VERSION 5.8 ;
BUSBITCHARS "[]" ;
DIVIDERCHAR "/" ;
UNITS
    DATABASE MICRONS 1000 ;
END UNITS

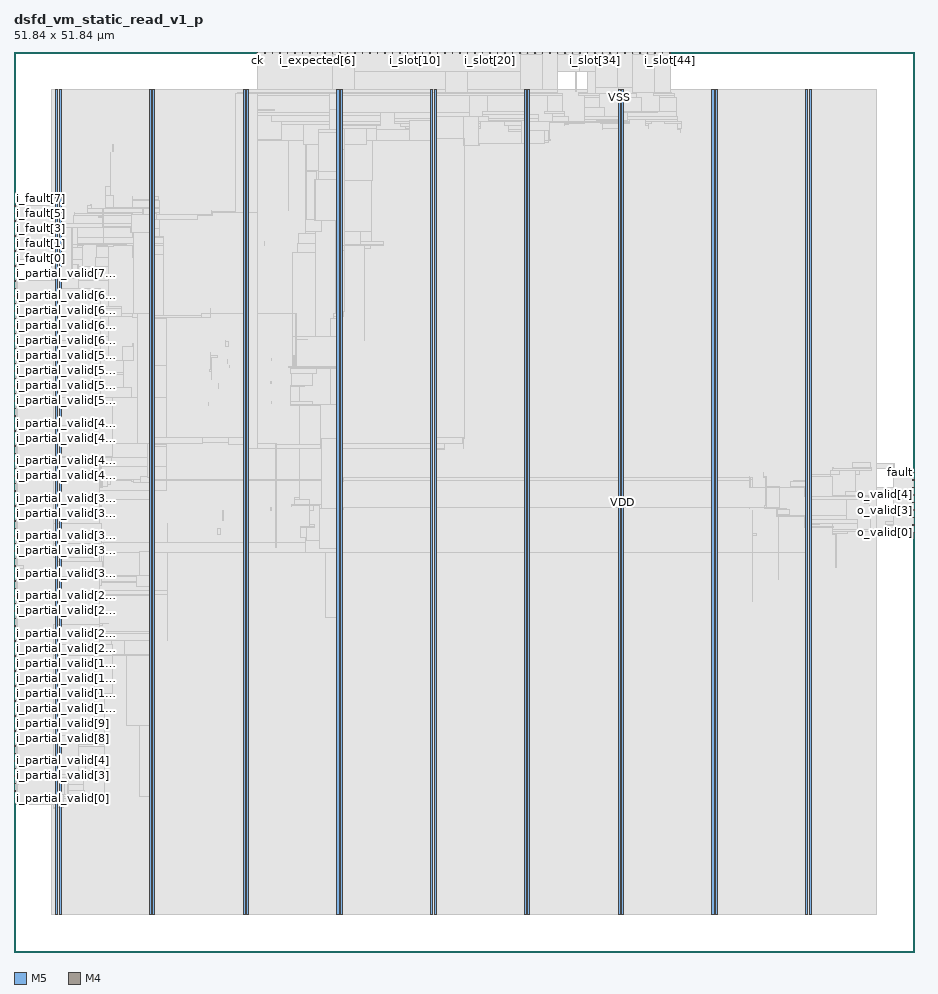
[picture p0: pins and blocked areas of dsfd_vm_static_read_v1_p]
MACRO dsfd_vm_static_read_v1_p
  FOREIGN dsfd_vm_static_read_v1_p 0 0 ;
  CLASS BLOCK ;
  SIZE 51.84 BY 51.84 ;
  PIN ck
    DIRECTION INPUT ;
    USE SIGNAL ;
    PORT
      LAYER M5 ;
        RECT  14.016 51.756 14.04 51.84 ;
    END
  END ck
  PIN fault
    DIRECTION OUTPUT ;
    USE SIGNAL ;
    PORT
      LAYER M4 ;
        RECT  51.756 27.6 51.84 27.624 ;
    END
  END fault
  PIN i_expected[0]
    DIRECTION INPUT ;
    USE SIGNAL ;
    PORT
      LAYER M5 ;
        RECT  14.88 51.756 14.904 51.84 ;
    END
  END i_expected[0]
  PIN i_expected[1]
    DIRECTION INPUT ;
    USE SIGNAL ;
    PORT
      LAYER M5 ;
        RECT  15.312 51.756 15.336 51.84 ;
    END
  END i_expected[1]
  PIN i_expected[2]
    DIRECTION INPUT ;
    USE SIGNAL ;
    PORT
      LAYER M5 ;
        RECT  15.744 51.756 15.768 51.84 ;
    END
  END i_expected[2]
  PIN i_expected[3]
    DIRECTION INPUT ;
    USE SIGNAL ;
    PORT
      LAYER M5 ;
        RECT  16.176 51.756 16.2 51.84 ;
    END
  END i_expected[3]
  PIN i_expected[4]
    DIRECTION INPUT ;
    USE SIGNAL ;
    PORT
      LAYER M5 ;
        RECT  16.608 51.756 16.632 51.84 ;
    END
  END i_expected[4]
  PIN i_expected[5]
    DIRECTION INPUT ;
    USE SIGNAL ;
    PORT
      LAYER M5 ;
        RECT  17.04 51.756 17.064 51.84 ;
    END
  END i_expected[5]
  PIN i_expected[6]
    DIRECTION INPUT ;
    USE SIGNAL ;
    PORT
      LAYER M5 ;
        RECT  17.472 51.756 17.496 51.84 ;
    END
  END i_expected[6]
  PIN i_expected[7]
    DIRECTION INPUT ;
    USE SIGNAL ;
    PORT
      LAYER M5 ;
        RECT  17.904 51.756 17.928 51.84 ;
    END
  END i_expected[7]
  PIN i_expected[8]
    DIRECTION INPUT ;
    USE SIGNAL ;
    PORT
      LAYER M5 ;
        RECT  18.336 51.756 18.36 51.84 ;
    END
  END i_expected[8]
  PIN i_fault[0]
    DIRECTION INPUT ;
    USE SIGNAL ;
    PORT
      LAYER M4 ;
        RECT  0 39.936 0.084 39.96 ;
    END
  END i_fault[0]
  PIN i_fault[1]
    DIRECTION INPUT ;
    USE SIGNAL ;
    PORT
      LAYER M4 ;
        RECT  0 40.368 0.084 40.392 ;
    END
  END i_fault[1]
  PIN i_fault[2]
    DIRECTION INPUT ;
    USE SIGNAL ;
    PORT
      LAYER M4 ;
        RECT  0 40.8 0.084 40.824 ;
    END
  END i_fault[2]
  PIN i_fault[3]
    DIRECTION INPUT ;
    USE SIGNAL ;
    PORT
      LAYER M4 ;
        RECT  0 41.232 0.084 41.256 ;
    END
  END i_fault[3]
  PIN i_fault[4]
    DIRECTION INPUT ;
    USE SIGNAL ;
    PORT
      LAYER M4 ;
        RECT  0 41.664 0.084 41.688 ;
    END
  END i_fault[4]
  PIN i_fault[5]
    DIRECTION INPUT ;
    USE SIGNAL ;
    PORT
      LAYER M4 ;
        RECT  0 42.096 0.084 42.12 ;
    END
  END i_fault[5]
  PIN i_fault[6]
    DIRECTION INPUT ;
    USE SIGNAL ;
    PORT
      LAYER M4 ;
        RECT  0 42.528 0.084 42.552 ;
    END
  END i_fault[6]
  PIN i_fault[7]
    DIRECTION INPUT ;
    USE SIGNAL ;
    PORT
      LAYER M4 ;
        RECT  0 42.96 0.084 42.984 ;
    END
  END i_fault[7]
  PIN i_partial_valid[0]
    DIRECTION INPUT ;
    USE SIGNAL ;
    PORT
      LAYER M4 ;
        RECT  0 8.832 0.084 8.856 ;
    END
  END i_partial_valid[0]
  PIN i_partial_valid[10]
    DIRECTION INPUT ;
    USE SIGNAL ;
    PORT
      LAYER M4 ;
        RECT  0 13.152 0.084 13.176 ;
    END
  END i_partial_valid[10]
  PIN i_partial_valid[11]
    DIRECTION INPUT ;
    USE SIGNAL ;
    PORT
      LAYER M4 ;
        RECT  0 13.584 0.084 13.608 ;
    END
  END i_partial_valid[11]
  PIN i_partial_valid[12]
    DIRECTION INPUT ;
    USE SIGNAL ;
    PORT
      LAYER M4 ;
        RECT  0 14.016 0.084 14.04 ;
    END
  END i_partial_valid[12]
  PIN i_partial_valid[13]
    DIRECTION INPUT ;
    USE SIGNAL ;
    PORT
      LAYER M4 ;
        RECT  0 14.448 0.084 14.472 ;
    END
  END i_partial_valid[13]
  PIN i_partial_valid[14]
    DIRECTION INPUT ;
    USE SIGNAL ;
    PORT
      LAYER M4 ;
        RECT  0 14.88 0.084 14.904 ;
    END
  END i_partial_valid[14]
  PIN i_partial_valid[15]
    DIRECTION INPUT ;
    USE SIGNAL ;
    PORT
      LAYER M4 ;
        RECT  0 15.312 0.084 15.336 ;
    END
  END i_partial_valid[15]
  PIN i_partial_valid[16]
    DIRECTION INPUT ;
    USE SIGNAL ;
    PORT
      LAYER M4 ;
        RECT  0 15.744 0.084 15.768 ;
    END
  END i_partial_valid[16]
  PIN i_partial_valid[17]
    DIRECTION INPUT ;
    USE SIGNAL ;
    PORT
      LAYER M4 ;
        RECT  0 16.176 0.084 16.2 ;
    END
  END i_partial_valid[17]
  PIN i_partial_valid[18]
    DIRECTION INPUT ;
    USE SIGNAL ;
    PORT
      LAYER M4 ;
        RECT  0 16.608 0.084 16.632 ;
    END
  END i_partial_valid[18]
  PIN i_partial_valid[19]
    DIRECTION INPUT ;
    USE SIGNAL ;
    PORT
      LAYER M4 ;
        RECT  0 17.04 0.084 17.064 ;
    END
  END i_partial_valid[19]
  PIN i_partial_valid[1]
    DIRECTION INPUT ;
    USE SIGNAL ;
    PORT
      LAYER M4 ;
        RECT  0 9.264 0.084 9.288 ;
    END
  END i_partial_valid[1]
  PIN i_partial_valid[20]
    DIRECTION INPUT ;
    USE SIGNAL ;
    PORT
      LAYER M4 ;
        RECT  0 17.472 0.084 17.496 ;
    END
  END i_partial_valid[20]
  PIN i_partial_valid[21]
    DIRECTION INPUT ;
    USE SIGNAL ;
    PORT
      LAYER M4 ;
        RECT  0 17.904 0.084 17.928 ;
    END
  END i_partial_valid[21]
  PIN i_partial_valid[22]
    DIRECTION INPUT ;
    USE SIGNAL ;
    PORT
      LAYER M4 ;
        RECT  0 18.336 0.084 18.36 ;
    END
  END i_partial_valid[22]
  PIN i_partial_valid[23]
    DIRECTION INPUT ;
    USE SIGNAL ;
    PORT
      LAYER M4 ;
        RECT  0 18.768 0.084 18.792 ;
    END
  END i_partial_valid[23]
  PIN i_partial_valid[24]
    DIRECTION INPUT ;
    USE SIGNAL ;
    PORT
      LAYER M4 ;
        RECT  0 19.2 0.084 19.224 ;
    END
  END i_partial_valid[24]
  PIN i_partial_valid[25]
    DIRECTION INPUT ;
    USE SIGNAL ;
    PORT
      LAYER M4 ;
        RECT  0 19.632 0.084 19.656 ;
    END
  END i_partial_valid[25]
  PIN i_partial_valid[26]
    DIRECTION INPUT ;
    USE SIGNAL ;
    PORT
      LAYER M4 ;
        RECT  0 20.064 0.084 20.088 ;
    END
  END i_partial_valid[26]
  PIN i_partial_valid[27]
    DIRECTION INPUT ;
    USE SIGNAL ;
    PORT
      LAYER M4 ;
        RECT  0 20.496 0.084 20.52 ;
    END
  END i_partial_valid[27]
  PIN i_partial_valid[28]
    DIRECTION INPUT ;
    USE SIGNAL ;
    PORT
      LAYER M4 ;
        RECT  0 20.928 0.084 20.952 ;
    END
  END i_partial_valid[28]
  PIN i_partial_valid[29]
    DIRECTION INPUT ;
    USE SIGNAL ;
    PORT
      LAYER M4 ;
        RECT  0 21.36 0.084 21.384 ;
    END
  END i_partial_valid[29]
  PIN i_partial_valid[2]
    DIRECTION INPUT ;
    USE SIGNAL ;
    PORT
      LAYER M4 ;
        RECT  0 9.696 0.084 9.72 ;
    END
  END i_partial_valid[2]
  PIN i_partial_valid[30]
    DIRECTION INPUT ;
    USE SIGNAL ;
    PORT
      LAYER M4 ;
        RECT  0 21.792 0.084 21.816 ;
    END
  END i_partial_valid[30]
  PIN i_partial_valid[31]
    DIRECTION INPUT ;
    USE SIGNAL ;
    PORT
      LAYER M4 ;
        RECT  0 22.224 0.084 22.248 ;
    END
  END i_partial_valid[31]
  PIN i_partial_valid[32]
    DIRECTION INPUT ;
    USE SIGNAL ;
    PORT
      LAYER M4 ;
        RECT  0 22.656 0.084 22.68 ;
    END
  END i_partial_valid[32]
  PIN i_partial_valid[33]
    DIRECTION INPUT ;
    USE SIGNAL ;
    PORT
      LAYER M4 ;
        RECT  0 23.088 0.084 23.112 ;
    END
  END i_partial_valid[33]
  PIN i_partial_valid[34]
    DIRECTION INPUT ;
    USE SIGNAL ;
    PORT
      LAYER M4 ;
        RECT  0 23.52 0.084 23.544 ;
    END
  END i_partial_valid[34]
  PIN i_partial_valid[35]
    DIRECTION INPUT ;
    USE SIGNAL ;
    PORT
      LAYER M4 ;
        RECT  0 23.952 0.084 23.976 ;
    END
  END i_partial_valid[35]
  PIN i_partial_valid[36]
    DIRECTION INPUT ;
    USE SIGNAL ;
    PORT
      LAYER M4 ;
        RECT  0 24.384 0.084 24.408 ;
    END
  END i_partial_valid[36]
  PIN i_partial_valid[37]
    DIRECTION INPUT ;
    USE SIGNAL ;
    PORT
      LAYER M4 ;
        RECT  0 24.816 0.084 24.84 ;
    END
  END i_partial_valid[37]
  PIN i_partial_valid[38]
    DIRECTION INPUT ;
    USE SIGNAL ;
    PORT
      LAYER M4 ;
        RECT  0 25.248 0.084 25.272 ;
    END
  END i_partial_valid[38]
  PIN i_partial_valid[39]
    DIRECTION INPUT ;
    USE SIGNAL ;
    PORT
      LAYER M4 ;
        RECT  0 25.68 0.084 25.704 ;
    END
  END i_partial_valid[39]
  PIN i_partial_valid[3]
    DIRECTION INPUT ;
    USE SIGNAL ;
    PORT
      LAYER M4 ;
        RECT  0 10.128 0.084 10.152 ;
    END
  END i_partial_valid[3]
  PIN i_partial_valid[40]
    DIRECTION INPUT ;
    USE SIGNAL ;
    PORT
      LAYER M4 ;
        RECT  0 26.112 0.084 26.136 ;
    END
  END i_partial_valid[40]
  PIN i_partial_valid[41]
    DIRECTION INPUT ;
    USE SIGNAL ;
    PORT
      LAYER M4 ;
        RECT  0 26.544 0.084 26.568 ;
    END
  END i_partial_valid[41]
  PIN i_partial_valid[42]
    DIRECTION INPUT ;
    USE SIGNAL ;
    PORT
      LAYER M4 ;
        RECT  0 26.976 0.084 27 ;
    END
  END i_partial_valid[42]
  PIN i_partial_valid[43]
    DIRECTION INPUT ;
    USE SIGNAL ;
    PORT
      LAYER M4 ;
        RECT  0 27.408 0.084 27.432 ;
    END
  END i_partial_valid[43]
  PIN i_partial_valid[44]
    DIRECTION INPUT ;
    USE SIGNAL ;
    PORT
      LAYER M4 ;
        RECT  0 27.84 0.084 27.864 ;
    END
  END i_partial_valid[44]
  PIN i_partial_valid[45]
    DIRECTION INPUT ;
    USE SIGNAL ;
    PORT
      LAYER M4 ;
        RECT  0 28.272 0.084 28.296 ;
    END
  END i_partial_valid[45]
  PIN i_partial_valid[46]
    DIRECTION INPUT ;
    USE SIGNAL ;
    PORT
      LAYER M4 ;
        RECT  0 28.704 0.084 28.728 ;
    END
  END i_partial_valid[46]
  PIN i_partial_valid[47]
    DIRECTION INPUT ;
    USE SIGNAL ;
    PORT
      LAYER M4 ;
        RECT  0 29.136 0.084 29.16 ;
    END
  END i_partial_valid[47]
  PIN i_partial_valid[48]
    DIRECTION INPUT ;
    USE SIGNAL ;
    PORT
      LAYER M4 ;
        RECT  0 29.568 0.084 29.592 ;
    END
  END i_partial_valid[48]
  PIN i_partial_valid[49]
    DIRECTION INPUT ;
    USE SIGNAL ;
    PORT
      LAYER M4 ;
        RECT  0 30 0.084 30.024 ;
    END
  END i_partial_valid[49]
  PIN i_partial_valid[4]
    DIRECTION INPUT ;
    USE SIGNAL ;
    PORT
      LAYER M4 ;
        RECT  0 10.56 0.084 10.584 ;
    END
  END i_partial_valid[4]
  PIN i_partial_valid[50]
    DIRECTION INPUT ;
    USE SIGNAL ;
    PORT
      LAYER M4 ;
        RECT  0 30.432 0.084 30.456 ;
    END
  END i_partial_valid[50]
  PIN i_partial_valid[51]
    DIRECTION INPUT ;
    USE SIGNAL ;
    PORT
      LAYER M4 ;
        RECT  0 30.864 0.084 30.888 ;
    END
  END i_partial_valid[51]
  PIN i_partial_valid[52]
    DIRECTION INPUT ;
    USE SIGNAL ;
    PORT
      LAYER M4 ;
        RECT  0 31.296 0.084 31.32 ;
    END
  END i_partial_valid[52]
  PIN i_partial_valid[53]
    DIRECTION INPUT ;
    USE SIGNAL ;
    PORT
      LAYER M4 ;
        RECT  0 31.728 0.084 31.752 ;
    END
  END i_partial_valid[53]
  PIN i_partial_valid[54]
    DIRECTION INPUT ;
    USE SIGNAL ;
    PORT
      LAYER M4 ;
        RECT  0 32.16 0.084 32.184 ;
    END
  END i_partial_valid[54]
  PIN i_partial_valid[55]
    DIRECTION INPUT ;
    USE SIGNAL ;
    PORT
      LAYER M4 ;
        RECT  0 32.592 0.084 32.616 ;
    END
  END i_partial_valid[55]
  PIN i_partial_valid[56]
    DIRECTION INPUT ;
    USE SIGNAL ;
    PORT
      LAYER M4 ;
        RECT  0 33.024 0.084 33.048 ;
    END
  END i_partial_valid[56]
  PIN i_partial_valid[57]
    DIRECTION INPUT ;
    USE SIGNAL ;
    PORT
      LAYER M4 ;
        RECT  0 33.456 0.084 33.48 ;
    END
  END i_partial_valid[57]
  PIN i_partial_valid[58]
    DIRECTION INPUT ;
    USE SIGNAL ;
    PORT
      LAYER M4 ;
        RECT  0 33.888 0.084 33.912 ;
    END
  END i_partial_valid[58]
  PIN i_partial_valid[59]
    DIRECTION INPUT ;
    USE SIGNAL ;
    PORT
      LAYER M4 ;
        RECT  0 34.32 0.084 34.344 ;
    END
  END i_partial_valid[59]
  PIN i_partial_valid[5]
    DIRECTION INPUT ;
    USE SIGNAL ;
    PORT
      LAYER M4 ;
        RECT  0 10.992 0.084 11.016 ;
    END
  END i_partial_valid[5]
  PIN i_partial_valid[60]
    DIRECTION INPUT ;
    USE SIGNAL ;
    PORT
      LAYER M4 ;
        RECT  0 34.752 0.084 34.776 ;
    END
  END i_partial_valid[60]
  PIN i_partial_valid[61]
    DIRECTION INPUT ;
    USE SIGNAL ;
    PORT
      LAYER M4 ;
        RECT  0 35.184 0.084 35.208 ;
    END
  END i_partial_valid[61]
  PIN i_partial_valid[62]
    DIRECTION INPUT ;
    USE SIGNAL ;
    PORT
      LAYER M4 ;
        RECT  0 35.616 0.084 35.64 ;
    END
  END i_partial_valid[62]
  PIN i_partial_valid[63]
    DIRECTION INPUT ;
    USE SIGNAL ;
    PORT
      LAYER M4 ;
        RECT  0 36.048 0.084 36.072 ;
    END
  END i_partial_valid[63]
  PIN i_partial_valid[64]
    DIRECTION INPUT ;
    USE SIGNAL ;
    PORT
      LAYER M4 ;
        RECT  0 36.48 0.084 36.504 ;
    END
  END i_partial_valid[64]
  PIN i_partial_valid[65]
    DIRECTION INPUT ;
    USE SIGNAL ;
    PORT
      LAYER M4 ;
        RECT  0 36.912 0.084 36.936 ;
    END
  END i_partial_valid[65]
  PIN i_partial_valid[66]
    DIRECTION INPUT ;
    USE SIGNAL ;
    PORT
      LAYER M4 ;
        RECT  0 37.344 0.084 37.368 ;
    END
  END i_partial_valid[66]
  PIN i_partial_valid[67]
    DIRECTION INPUT ;
    USE SIGNAL ;
    PORT
      LAYER M4 ;
        RECT  0 37.776 0.084 37.8 ;
    END
  END i_partial_valid[67]
  PIN i_partial_valid[68]
    DIRECTION INPUT ;
    USE SIGNAL ;
    PORT
      LAYER M4 ;
        RECT  0 38.208 0.084 38.232 ;
    END
  END i_partial_valid[68]
  PIN i_partial_valid[69]
    DIRECTION INPUT ;
    USE SIGNAL ;
    PORT
      LAYER M4 ;
        RECT  0 38.64 0.084 38.664 ;
    END
  END i_partial_valid[69]
  PIN i_partial_valid[6]
    DIRECTION INPUT ;
    USE SIGNAL ;
    PORT
      LAYER M4 ;
        RECT  0 11.424 0.084 11.448 ;
    END
  END i_partial_valid[6]
  PIN i_partial_valid[70]
    DIRECTION INPUT ;
    USE SIGNAL ;
    PORT
      LAYER M4 ;
        RECT  0 39.072 0.084 39.096 ;
    END
  END i_partial_valid[70]
  PIN i_partial_valid[71]
    DIRECTION INPUT ;
    USE SIGNAL ;
    PORT
      LAYER M4 ;
        RECT  0 39.504 0.084 39.528 ;
    END
  END i_partial_valid[71]
  PIN i_partial_valid[7]
    DIRECTION INPUT ;
    USE SIGNAL ;
    PORT
      LAYER M4 ;
        RECT  0 11.856 0.084 11.88 ;
    END
  END i_partial_valid[7]
  PIN i_partial_valid[8]
    DIRECTION INPUT ;
    USE SIGNAL ;
    PORT
      LAYER M4 ;
        RECT  0 12.288 0.084 12.312 ;
    END
  END i_partial_valid[8]
  PIN i_partial_valid[9]
    DIRECTION INPUT ;
    USE SIGNAL ;
    PORT
      LAYER M4 ;
        RECT  0 12.72 0.084 12.744 ;
    END
  END i_partial_valid[9]
  PIN i_slot[0]
    DIRECTION INPUT ;
    USE SIGNAL ;
    PORT
      LAYER M5 ;
        RECT  18.768 51.756 18.792 51.84 ;
    END
  END i_slot[0]
  PIN i_slot[10]
    DIRECTION INPUT ;
    USE SIGNAL ;
    PORT
      LAYER M5 ;
        RECT  23.088 51.756 23.112 51.84 ;
    END
  END i_slot[10]
  PIN i_slot[11]
    DIRECTION INPUT ;
    USE SIGNAL ;
    PORT
      LAYER M5 ;
        RECT  23.52 51.756 23.544 51.84 ;
    END
  END i_slot[11]
  PIN i_slot[12]
    DIRECTION INPUT ;
    USE SIGNAL ;
    PORT
      LAYER M5 ;
        RECT  23.952 51.756 23.976 51.84 ;
    END
  END i_slot[12]
  PIN i_slot[13]
    DIRECTION INPUT ;
    USE SIGNAL ;
    PORT
      LAYER M5 ;
        RECT  24.384 51.756 24.408 51.84 ;
    END
  END i_slot[13]
  PIN i_slot[14]
    DIRECTION INPUT ;
    USE SIGNAL ;
    PORT
      LAYER M5 ;
        RECT  24.816 51.756 24.84 51.84 ;
    END
  END i_slot[14]
  PIN i_slot[15]
    DIRECTION INPUT ;
    USE SIGNAL ;
    PORT
      LAYER M5 ;
        RECT  25.248 51.756 25.272 51.84 ;
    END
  END i_slot[15]
  PIN i_slot[16]
    DIRECTION INPUT ;
    USE SIGNAL ;
    PORT
      LAYER M5 ;
        RECT  25.68 51.756 25.704 51.84 ;
    END
  END i_slot[16]
  PIN i_slot[17]
    DIRECTION INPUT ;
    USE SIGNAL ;
    PORT
      LAYER M5 ;
        RECT  26.112 51.756 26.136 51.84 ;
    END
  END i_slot[17]
  PIN i_slot[18]
    DIRECTION INPUT ;
    USE SIGNAL ;
    PORT
      LAYER M5 ;
        RECT  26.544 51.756 26.568 51.84 ;
    END
  END i_slot[18]
  PIN i_slot[19]
    DIRECTION INPUT ;
    USE SIGNAL ;
    PORT
      LAYER M5 ;
        RECT  26.976 51.756 27 51.84 ;
    END
  END i_slot[19]
  PIN i_slot[1]
    DIRECTION INPUT ;
    USE SIGNAL ;
    PORT
      LAYER M5 ;
        RECT  19.2 51.756 19.224 51.84 ;
    END
  END i_slot[1]
  PIN i_slot[20]
    DIRECTION INPUT ;
    USE SIGNAL ;
    PORT
      LAYER M5 ;
        RECT  27.408 51.756 27.432 51.84 ;
    END
  END i_slot[20]
  PIN i_slot[21]
    DIRECTION INPUT ;
    USE SIGNAL ;
    PORT
      LAYER M5 ;
        RECT  27.84 51.756 27.864 51.84 ;
    END
  END i_slot[21]
  PIN i_slot[22]
    DIRECTION INPUT ;
    USE SIGNAL ;
    PORT
      LAYER M5 ;
        RECT  28.272 51.756 28.296 51.84 ;
    END
  END i_slot[22]
  PIN i_slot[23]
    DIRECTION INPUT ;
    USE SIGNAL ;
    PORT
      LAYER M5 ;
        RECT  28.704 51.756 28.728 51.84 ;
    END
  END i_slot[23]
  PIN i_slot[24]
    DIRECTION INPUT ;
    USE SIGNAL ;
    PORT
      LAYER M5 ;
        RECT  29.136 51.756 29.16 51.84 ;
    END
  END i_slot[24]
  PIN i_slot[25]
    DIRECTION INPUT ;
    USE SIGNAL ;
    PORT
      LAYER M5 ;
        RECT  29.568 51.756 29.592 51.84 ;
    END
  END i_slot[25]
  PIN i_slot[26]
    DIRECTION INPUT ;
    USE SIGNAL ;
    PORT
      LAYER M5 ;
        RECT  30 51.756 30.024 51.84 ;
    END
  END i_slot[26]
  PIN i_slot[27]
    DIRECTION INPUT ;
    USE SIGNAL ;
    PORT
      LAYER M5 ;
        RECT  30.432 51.756 30.456 51.84 ;
    END
  END i_slot[27]
  PIN i_slot[28]
    DIRECTION INPUT ;
    USE SIGNAL ;
    PORT
      LAYER M5 ;
        RECT  30.864 51.756 30.888 51.84 ;
    END
  END i_slot[28]
  PIN i_slot[29]
    DIRECTION INPUT ;
    USE SIGNAL ;
    PORT
      LAYER M5 ;
        RECT  31.296 51.756 31.32 51.84 ;
    END
  END i_slot[29]
  PIN i_slot[2]
    DIRECTION INPUT ;
    USE SIGNAL ;
    PORT
      LAYER M5 ;
        RECT  19.632 51.756 19.656 51.84 ;
    END
  END i_slot[2]
  PIN i_slot[30]
    DIRECTION INPUT ;
    USE SIGNAL ;
    PORT
      LAYER M5 ;
        RECT  31.728 51.756 31.752 51.84 ;
    END
  END i_slot[30]
  PIN i_slot[31]
    DIRECTION INPUT ;
    USE SIGNAL ;
    PORT
      LAYER M5 ;
        RECT  32.16 51.756 32.184 51.84 ;
    END
  END i_slot[31]
  PIN i_slot[32]
    DIRECTION INPUT ;
    USE SIGNAL ;
    PORT
      LAYER M5 ;
        RECT  32.592 51.756 32.616 51.84 ;
    END
  END i_slot[32]
  PIN i_slot[33]
    DIRECTION INPUT ;
    USE SIGNAL ;
    PORT
      LAYER M5 ;
        RECT  33.024 51.756 33.048 51.84 ;
    END
  END i_slot[33]
  PIN i_slot[34]
    DIRECTION INPUT ;
    USE SIGNAL ;
    PORT
      LAYER M5 ;
        RECT  33.456 51.756 33.48 51.84 ;
    END
  END i_slot[34]
  PIN i_slot[35]
    DIRECTION INPUT ;
    USE SIGNAL ;
    PORT
      LAYER M5 ;
        RECT  33.888 51.756 33.912 51.84 ;
    END
  END i_slot[35]
  PIN i_slot[36]
    DIRECTION INPUT ;
    USE SIGNAL ;
    PORT
      LAYER M5 ;
        RECT  34.32 51.756 34.344 51.84 ;
    END
  END i_slot[36]
  PIN i_slot[37]
    DIRECTION INPUT ;
    USE SIGNAL ;
    PORT
      LAYER M5 ;
        RECT  34.752 51.756 34.776 51.84 ;
    END
  END i_slot[37]
  PIN i_slot[38]
    DIRECTION INPUT ;
    USE SIGNAL ;
    PORT
      LAYER M5 ;
        RECT  35.184 51.756 35.208 51.84 ;
    END
  END i_slot[38]
  PIN i_slot[39]
    DIRECTION INPUT ;
    USE SIGNAL ;
    PORT
      LAYER M5 ;
        RECT  35.616 51.756 35.64 51.84 ;
    END
  END i_slot[39]
  PIN i_slot[3]
    DIRECTION INPUT ;
    USE SIGNAL ;
    PORT
      LAYER M5 ;
        RECT  20.064 51.756 20.088 51.84 ;
    END
  END i_slot[3]
  PIN i_slot[40]
    DIRECTION INPUT ;
    USE SIGNAL ;
    PORT
      LAYER M5 ;
        RECT  36.048 51.756 36.072 51.84 ;
    END
  END i_slot[40]
  PIN i_slot[41]
    DIRECTION INPUT ;
    USE SIGNAL ;
    PORT
      LAYER M5 ;
        RECT  36.48 51.756 36.504 51.84 ;
    END
  END i_slot[41]
  PIN i_slot[42]
    DIRECTION INPUT ;
    USE SIGNAL ;
    PORT
      LAYER M5 ;
        RECT  36.912 51.756 36.936 51.84 ;
    END
  END i_slot[42]
  PIN i_slot[43]
    DIRECTION INPUT ;
    USE SIGNAL ;
    PORT
      LAYER M5 ;
        RECT  37.344 51.756 37.368 51.84 ;
    END
  END i_slot[43]
  PIN i_slot[44]
    DIRECTION INPUT ;
    USE SIGNAL ;
    PORT
      LAYER M5 ;
        RECT  37.776 51.756 37.8 51.84 ;
    END
  END i_slot[44]
  PIN i_slot[4]
    DIRECTION INPUT ;
    USE SIGNAL ;
    PORT
      LAYER M5 ;
        RECT  20.496 51.756 20.52 51.84 ;
    END
  END i_slot[4]
  PIN i_slot[5]
    DIRECTION INPUT ;
    USE SIGNAL ;
    PORT
      LAYER M5 ;
        RECT  20.928 51.756 20.952 51.84 ;
    END
  END i_slot[5]
  PIN i_slot[6]
    DIRECTION INPUT ;
    USE SIGNAL ;
    PORT
      LAYER M5 ;
        RECT  21.36 51.756 21.384 51.84 ;
    END
  END i_slot[6]
  PIN i_slot[7]
    DIRECTION INPUT ;
    USE SIGNAL ;
    PORT
      LAYER M5 ;
        RECT  21.792 51.756 21.816 51.84 ;
    END
  END i_slot[7]
  PIN i_slot[8]
    DIRECTION INPUT ;
    USE SIGNAL ;
    PORT
      LAYER M5 ;
        RECT  22.224 51.756 22.248 51.84 ;
    END
  END i_slot[8]
  PIN i_slot[9]
    DIRECTION INPUT ;
    USE SIGNAL ;
    PORT
      LAYER M5 ;
        RECT  22.656 51.756 22.68 51.84 ;
    END
  END i_slot[9]
  PIN o_valid[0]
    DIRECTION OUTPUT ;
    USE SIGNAL ;
    PORT
      LAYER M4 ;
        RECT  51.756 24.144 51.84 24.168 ;
    END
  END o_valid[0]
  PIN o_valid[1]
    DIRECTION OUTPUT ;
    USE SIGNAL ;
    PORT
      LAYER M4 ;
        RECT  51.756 24.576 51.84 24.6 ;
    END
  END o_valid[1]
  PIN o_valid[2]
    DIRECTION OUTPUT ;
    USE SIGNAL ;
    PORT
      LAYER M4 ;
        RECT  51.756 25.008 51.84 25.032 ;
    END
  END o_valid[2]
  PIN o_valid[3]
    DIRECTION OUTPUT ;
    USE SIGNAL ;
    PORT
      LAYER M4 ;
        RECT  51.756 25.44 51.84 25.464 ;
    END
  END o_valid[3]
  PIN o_valid[4]
    DIRECTION OUTPUT ;
    USE SIGNAL ;
    PORT
      LAYER M4 ;
        RECT  51.756 25.872 51.84 25.896 ;
    END
  END o_valid[4]
  PIN o_valid[5]
    DIRECTION OUTPUT ;
    USE SIGNAL ;
    PORT
      LAYER M4 ;
        RECT  51.756 26.304 51.84 26.328 ;
    END
  END o_valid[5]
  PIN o_valid[6]
    DIRECTION OUTPUT ;
    USE SIGNAL ;
    PORT
      LAYER M4 ;
        RECT  51.756 26.736 51.84 26.76 ;
    END
  END o_valid[6]
  PIN o_valid[7]
    DIRECTION OUTPUT ;
    USE SIGNAL ;
    PORT
      LAYER M4 ;
        RECT  51.756 27.168 51.84 27.192 ;
    END
  END o_valid[7]
  PIN rst_n
    DIRECTION INPUT ;
    USE SIGNAL ;
    PORT
      LAYER M5 ;
        RECT  14.448 51.756 14.472 51.84 ;
    END
  END rst_n
  PIN VDD
    DIRECTION INOUT ;
    USE POWER ;
    PORT
      LAYER M5 ;
        RECT  45.792 2.151 45.912 49.689 ;
        RECT  40.392 2.151 40.512 49.689 ;
        RECT  34.992 2.151 35.112 49.689 ;
        RECT  29.592 2.151 29.712 49.689 ;
        RECT  24.192 2.151 24.312 49.689 ;
        RECT  18.792 2.151 18.912 49.689 ;
        RECT  13.392 2.151 13.512 49.689 ;
        RECT  7.992 2.151 8.112 49.689 ;
        RECT  2.592 2.151 2.712 49.689 ;
    END
  END VDD
  PIN VSS
    DIRECTION INOUT ;
    USE GROUND ;
    PORT
      LAYER M5 ;
        RECT  45.6 2.137 45.72 49.703 ;
        RECT  40.2 2.137 40.32 49.703 ;
        RECT  34.8 2.137 34.92 49.703 ;
        RECT  29.4 2.137 29.52 49.703 ;
        RECT  24 2.137 24.12 49.703 ;
        RECT  18.6 2.137 18.72 49.703 ;
        RECT  13.2 2.137 13.32 49.703 ;
        RECT  7.8 2.137 7.92 49.703 ;
        RECT  2.4 2.137 2.52 49.703 ;
    END
  END VSS
  # OT_OBS_CLOSED layer=M5 d_um=1.536 added=41
  OBS
    LAYER RVTN ;
     RECT  2.16 2.16 49.68 2.295 ;
     RECT  2.16 2.565 49.68 2.835 ;
     RECT  2.16 3.105 49.68 3.375 ;
     RECT  2.16 3.645 49.68 3.915 ;
     RECT  2.16 4.185 49.68 4.455 ;
     RECT  2.16 4.725 49.68 4.995 ;
     RECT  2.16 5.265 49.68 5.535 ;
     RECT  2.16 5.805 49.68 6.075 ;
     RECT  2.16 6.345 49.68 6.615 ;
     RECT  2.16 6.885 49.68 7.155 ;
     RECT  2.16 7.425 49.68 7.695 ;
     RECT  2.16 7.965 49.68 8.235 ;
     RECT  2.16 8.505 49.68 8.775 ;
     RECT  2.16 9.045 49.68 9.315 ;
     RECT  2.16 9.585 49.68 9.855 ;
     RECT  2.16 10.125 49.68 10.395 ;
     RECT  2.16 10.665 49.68 10.935 ;
     RECT  2.16 11.205 49.68 11.475 ;
     RECT  2.16 11.745 49.68 12.015 ;
     RECT  2.16 12.285 49.68 12.555 ;
     RECT  2.16 12.825 49.68 13.095 ;
     RECT  2.16 13.365 49.68 13.635 ;
     RECT  2.16 13.905 49.68 14.175 ;
     RECT  2.16 14.445 49.68 14.715 ;
     RECT  2.16 14.985 49.68 15.255 ;
     RECT  2.16 15.525 49.68 15.795 ;
     RECT  2.16 16.065 49.68 16.335 ;
     RECT  2.16 16.605 49.68 16.875 ;
     RECT  2.16 17.145 49.68 17.415 ;
     RECT  2.16 17.685 49.68 17.955 ;
     RECT  2.16 18.225 49.68 18.495 ;
     RECT  2.16 18.765 49.68 19.035 ;
     RECT  2.16 19.305 49.68 19.575 ;
     RECT  2.16 19.845 49.68 20.115 ;
     RECT  2.16 20.385 49.68 20.655 ;
     RECT  2.16 20.925 49.68 21.195 ;
     RECT  2.16 21.465 49.68 21.735 ;
     RECT  2.16 22.005 49.68 22.275 ;
     RECT  2.16 22.545 49.68 22.815 ;
     RECT  2.16 23.085 49.68 23.355 ;
     RECT  2.16 23.625 49.68 23.895 ;
     RECT  2.16 24.165 49.68 24.435 ;
     RECT  2.16 24.705 49.68 24.975 ;
     RECT  2.16 25.245 49.68 25.515 ;
     RECT  2.16 25.785 49.68 26.055 ;
     RECT  2.16 26.325 49.68 26.595 ;
     RECT  2.16 26.865 49.68 27.135 ;
     RECT  2.16 27.405 49.68 27.675 ;
     RECT  2.16 27.945 49.68 28.215 ;
     RECT  2.16 28.485 49.68 28.755 ;
     RECT  2.16 29.025 49.68 29.295 ;
     RECT  2.16 29.565 49.68 29.835 ;
     RECT  2.16 30.105 49.68 30.375 ;
     RECT  2.16 30.645 49.68 30.915 ;
     RECT  2.16 31.185 49.68 31.455 ;
     RECT  2.16 31.725 49.68 31.995 ;
     RECT  2.16 32.265 49.68 32.535 ;
     RECT  2.16 32.805 49.68 33.075 ;
     RECT  2.16 33.345 49.68 33.615 ;
     RECT  2.16 33.885 49.68 34.155 ;
     RECT  2.16 34.425 49.68 34.695 ;
     RECT  2.16 34.965 49.68 35.235 ;
     RECT  2.16 35.505 49.68 35.775 ;
     RECT  2.16 36.045 49.68 36.315 ;
     RECT  2.16 36.585 49.68 36.855 ;
     RECT  2.16 37.125 49.68 37.395 ;
     RECT  2.16 37.665 49.68 37.935 ;
     RECT  2.16 38.205 49.68 38.475 ;
     RECT  2.16 38.745 49.68 39.015 ;
     RECT  2.16 39.285 49.68 39.555 ;
     RECT  2.16 39.825 49.68 40.095 ;
     RECT  2.16 40.365 49.68 40.635 ;
     RECT  2.16 40.905 49.68 41.175 ;
     RECT  2.16 41.445 49.68 41.715 ;
     RECT  2.16 41.985 49.68 42.255 ;
     RECT  2.16 42.525 49.68 42.795 ;
     RECT  2.16 43.065 49.68 43.335 ;
     RECT  2.16 43.605 49.68 43.875 ;
     RECT  2.16 44.145 49.68 44.415 ;
     RECT  2.16 44.685 49.68 44.955 ;
     RECT  2.16 45.225 49.68 45.495 ;
     RECT  2.16 45.765 49.68 46.035 ;
     RECT  2.16 46.305 49.68 46.575 ;
     RECT  2.16 46.845 49.68 47.115 ;
     RECT  2.16 47.385 49.68 47.655 ;
     RECT  2.16 47.925 49.68 48.195 ;
     RECT  2.16 48.465 49.68 48.735 ;
     RECT  2.16 49.005 49.68 49.275 ;
     RECT  2.16 49.545 49.68 49.68 ;
    LAYER RVTP ;
     RECT  2.16 2.295 49.68 2.565 ;
     RECT  2.16 2.835 49.68 3.105 ;
     RECT  2.16 3.375 49.68 3.645 ;
     RECT  2.16 3.915 49.68 4.185 ;
     RECT  2.16 4.455 49.68 4.725 ;
     RECT  2.16 4.995 49.68 5.265 ;
     RECT  2.16 5.535 49.68 5.805 ;
     RECT  2.16 6.075 49.68 6.345 ;
     RECT  2.16 6.615 49.68 6.885 ;
     RECT  2.16 7.155 49.68 7.425 ;
     RECT  2.16 7.695 49.68 7.965 ;
     RECT  2.16 8.235 49.68 8.505 ;
     RECT  2.16 8.775 49.68 9.045 ;
     RECT  2.16 9.315 49.68 9.585 ;
     RECT  2.16 9.855 49.68 10.125 ;
     RECT  2.16 10.395 49.68 10.665 ;
     RECT  2.16 10.935 49.68 11.205 ;
     RECT  2.16 11.475 49.68 11.745 ;
     RECT  2.16 12.015 49.68 12.285 ;
     RECT  2.16 12.555 49.68 12.825 ;
     RECT  2.16 13.095 49.68 13.365 ;
     RECT  2.16 13.635 49.68 13.905 ;
     RECT  2.16 14.175 49.68 14.445 ;
     RECT  2.16 14.715 49.68 14.985 ;
     RECT  2.16 15.255 49.68 15.525 ;
     RECT  2.16 15.795 49.68 16.065 ;
     RECT  2.16 16.335 49.68 16.605 ;
     RECT  2.16 16.875 49.68 17.145 ;
     RECT  2.16 17.415 49.68 17.685 ;
     RECT  2.16 17.955 49.68 18.225 ;
     RECT  2.16 18.495 49.68 18.765 ;
     RECT  2.16 19.035 49.68 19.305 ;
     RECT  2.16 19.575 49.68 19.845 ;
     RECT  2.16 20.115 49.68 20.385 ;
     RECT  2.16 20.655 49.68 20.925 ;
     RECT  2.16 21.195 49.68 21.465 ;
     RECT  2.16 21.735 49.68 22.005 ;
     RECT  2.16 22.275 49.68 22.545 ;
     RECT  2.16 22.815 49.68 23.085 ;
     RECT  2.16 23.355 49.68 23.625 ;
     RECT  2.16 23.895 49.68 24.165 ;
     RECT  2.16 24.435 49.68 24.705 ;
     RECT  2.16 24.975 49.68 25.245 ;
     RECT  2.16 25.515 49.68 25.785 ;
     RECT  2.16 26.055 49.68 26.325 ;
     RECT  2.16 26.595 49.68 26.865 ;
     RECT  2.16 27.135 49.68 27.405 ;
     RECT  2.16 27.675 49.68 27.945 ;
     RECT  2.16 28.215 49.68 28.485 ;
     RECT  2.16 28.755 49.68 29.025 ;
     RECT  2.16 29.295 49.68 29.565 ;
     RECT  2.16 29.835 49.68 30.105 ;
     RECT  2.16 30.375 49.68 30.645 ;
     RECT  2.16 30.915 49.68 31.185 ;
     RECT  2.16 31.455 49.68 31.725 ;
     RECT  2.16 31.995 49.68 32.265 ;
     RECT  2.16 32.535 49.68 32.805 ;
     RECT  2.16 33.075 49.68 33.345 ;
     RECT  2.16 33.615 49.68 33.885 ;
     RECT  2.16 34.155 49.68 34.425 ;
     RECT  2.16 34.695 49.68 34.965 ;
     RECT  2.16 35.235 49.68 35.505 ;
     RECT  2.16 35.775 49.68 36.045 ;
     RECT  2.16 36.315 49.68 36.585 ;
     RECT  2.16 36.855 49.68 37.125 ;
     RECT  2.16 37.395 49.68 37.665 ;
     RECT  2.16 37.935 49.68 38.205 ;
     RECT  2.16 38.475 49.68 38.745 ;
     RECT  2.16 39.015 49.68 39.285 ;
     RECT  2.16 39.555 49.68 39.825 ;
     RECT  2.16 40.095 49.68 40.365 ;
     RECT  2.16 40.635 49.68 40.905 ;
     RECT  2.16 41.175 49.68 41.445 ;
     RECT  2.16 41.715 49.68 41.985 ;
     RECT  2.16 42.255 49.68 42.525 ;
     RECT  2.16 42.795 49.68 43.065 ;
     RECT  2.16 43.335 49.68 43.605 ;
     RECT  2.16 43.875 49.68 44.145 ;
     RECT  2.16 44.415 49.68 44.685 ;
     RECT  2.16 44.955 49.68 45.225 ;
     RECT  2.16 45.495 49.68 45.765 ;
     RECT  2.16 46.035 49.68 46.305 ;
     RECT  2.16 46.575 49.68 46.845 ;
     RECT  2.16 47.115 49.68 47.385 ;
     RECT  2.16 47.655 49.68 47.925 ;
     RECT  2.16 48.195 49.68 48.465 ;
     RECT  2.16 48.735 49.68 49.005 ;
     RECT  2.16 49.275 49.68 49.545 ;
    LAYER M1 ;
     RECT  2.16 2.151 49.68 49.689 ;
    LAYER M2 ;
     RECT  0.535 23.436 2.16 23.454 ;
     RECT  0.103 39.87 2.16 39.888 ;
     RECT  2.16 2.151 49.68 49.689 ;
     RECT  49.68 27.846 50.675 28.134 ;
     RECT  49.68 24.138 50.711 25.434 ;
     RECT  49.68 26.226 50.711 26.784 ;
     RECT  50.675 28.116 50.711 28.134 ;
    LAYER M3 ;
     RECT  2.415 2.143 2.505 2.413 ;
     RECT  7.815 2.143 7.905 2.413 ;
     RECT  13.215 2.143 13.305 2.413 ;
     RECT  18.615 2.143 18.705 2.413 ;
     RECT  24.015 2.143 24.105 2.413 ;
     RECT  29.415 2.143 29.505 2.413 ;
     RECT  34.815 2.143 34.905 2.413 ;
     RECT  40.215 2.143 40.305 2.413 ;
     RECT  45.615 2.143 45.705 2.413 ;
     RECT  2.415 2.413 2.697 8.275 ;
     RECT  2.304 8.275 2.697 8.311 ;
     RECT  2.304 8.311 2.79 8.735 ;
     RECT  2.34 8.735 2.79 8.815 ;
     RECT  3.564 8.779 3.582 8.815 ;
     RECT  7.815 2.413 8.097 8.941 ;
     RECT  2.34 8.815 3.582 8.977 ;
     RECT  2.34 8.977 4.086 9.275 ;
     RECT  2.34 9.275 4.014 9.625 ;
     RECT  2.304 9.625 4.014 10.471 ;
     RECT  2.304 10.471 4.122 11.011 ;
     RECT  2.304 11.011 4.338 11.021 ;
     RECT  2.34 11.021 4.338 11.281 ;
     RECT  5.184 8.851 5.202 11.281 ;
     RECT  2.34 11.281 5.202 11.851 ;
     RECT  2.268 11.851 5.202 11.975 ;
     RECT  7.2 8.941 8.097 13.027 ;
     RECT  2.304 11.975 5.202 17.077 ;
     RECT  6.48 13.027 8.097 17.077 ;
     RECT  2.304 17.077 8.097 17.117 ;
     RECT  2.304 17.117 5.634 17.923 ;
     RECT  6.372 17.117 8.097 17.923 ;
     RECT  2.304 17.923 8.097 18.331 ;
     RECT  2.268 18.331 8.097 18.455 ;
     RECT  18.615 2.413 18.897 19.273 ;
     RECT  2.304 18.455 8.097 20.525 ;
     RECT  2.376 20.525 8.097 20.587 ;
     RECT  8.82 17.959 8.838 20.587 ;
     RECT  2.376 20.587 8.838 20.849 ;
     RECT  2.376 20.849 8.097 21.271 ;
     RECT  2.34 21.271 8.097 21.355 ;
     RECT  45.615 2.413 45.897 22.987 ;
     RECT  45.612 22.987 45.897 23.117 ;
     RECT  17.928 19.273 18.897 23.251 ;
     RECT  17.604 23.251 18.897 23.309 ;
     RECT  11.484 23.035 11.502 23.323 ;
     RECT  11.412 23.323 11.502 23.549 ;
     RECT  16.812 23.317 16.83 23.899 ;
     RECT  42.516 20.191 42.534 23.971 ;
     RECT  47.34 22.171 47.358 24.061 ;
     RECT  42.516 23.971 42.786 24.089 ;
     RECT  47.124 24.061 47.358 24.097 ;
     RECT  17.928 23.309 18.897 24.241 ;
     RECT  47.124 24.097 48.006 24.241 ;
     RECT  49.32 24.205 49.338 24.241 ;
     RECT  17.712 24.241 18.897 24.359 ;
     RECT  47.124 24.241 49.338 24.359 ;
     RECT  11.736 24.061 11.898 24.395 ;
     RECT  0.54 23.431 0.558 24.413 ;
     RECT  16.488 23.899 16.83 24.439 ;
     RECT  45.615 23.117 45.897 24.475 ;
     RECT  16.488 24.439 17.298 24.503 ;
     RECT  50.688 24.133 50.706 24.571 ;
     RECT  16.992 24.503 17.298 24.629 ;
     RECT  45.54 24.475 45.897 24.637 ;
     RECT  45.54 24.637 46.386 24.673 ;
     RECT  47.124 24.359 48.582 24.673 ;
     RECT  8.82 20.849 8.838 24.701 ;
     RECT  50.184 24.571 50.706 24.809 ;
     RECT  45.54 24.673 48.582 24.899 ;
     RECT  44.028 21.433 44.046 25.099 ;
     RECT  45.54 24.899 47.934 25.133 ;
     RECT  49.32 24.359 49.338 25.169 ;
     RECT  43.92 25.099 44.046 25.177 ;
     RECT  12.024 24.871 12.042 25.439 ;
     RECT  42.516 24.089 42.534 25.439 ;
     RECT  16.992 24.629 17.01 25.447 ;
     RECT  43.92 25.177 44.694 25.475 ;
     RECT  18.216 24.359 18.897 25.483 ;
     RECT  43.92 25.475 44.514 25.519 ;
     RECT  43.308 25.519 44.514 25.547 ;
     RECT  43.308 25.547 44.118 25.555 ;
     RECT  14.796 25.447 14.814 25.583 ;
     RECT  18.216 25.483 18.99 25.613 ;
     RECT  42.372 25.555 42.39 25.613 ;
     RECT  43.2 25.555 44.118 25.613 ;
     RECT  16.992 25.447 17.262 25.709 ;
     RECT  43.2 25.613 43.326 25.709 ;
     RECT  49.284 25.555 49.302 25.709 ;
     RECT  16.992 25.709 17.01 25.717 ;
     RECT  15.984 25.681 16.002 25.753 ;
     RECT  16.776 25.717 17.01 25.753 ;
     RECT  15.984 25.753 17.01 25.757 ;
     RECT  2.304 21.355 8.097 26.059 ;
     RECT  45.615 25.133 47.934 26.059 ;
     RECT  48.996 25.825 49.23 26.059 ;
     RECT  16.128 25.757 17.01 26.087 ;
     RECT  16.128 26.087 16.47 26.159 ;
     RECT  45.615 26.059 49.23 26.251 ;
     RECT  45.54 26.251 49.23 26.285 ;
     RECT  50.688 24.809 50.706 26.299 ;
     RECT  50.148 26.299 50.706 26.357 ;
     RECT  45.54 26.285 47.034 26.519 ;
     RECT  47.88 26.285 48.798 26.519 ;
     RECT  45.54 26.519 46.854 26.555 ;
     RECT  2.268 26.059 8.097 26.599 ;
     RECT  43.308 25.709 43.326 26.731 ;
     RECT  44.1 25.613 44.118 26.731 ;
     RECT  43.308 26.731 44.118 26.789 ;
     RECT  50.688 26.357 50.706 26.789 ;
     RECT  44.748 26.797 44.766 26.833 ;
     RECT  45.54 26.555 46.53 26.833 ;
     RECT  44.748 26.833 46.53 27.095 ;
     RECT  18.216 25.613 18.897 27.115 ;
     RECT  42.372 26.731 42.39 27.163 ;
     RECT  44.892 27.095 46.53 27.167 ;
     RECT  42.372 27.163 42.534 27.329 ;
     RECT  43.308 26.789 43.326 27.337 ;
     RECT  18.216 27.115 18.99 27.341 ;
     RECT  45.615 27.167 46.53 27.355 ;
     RECT  42.372 27.329 42.39 27.365 ;
     RECT  43.164 27.337 43.326 27.401 ;
     RECT  45.615 27.355 47.034 27.481 ;
     RECT  48.456 26.519 48.474 27.481 ;
     RECT  45.615 27.481 47.574 27.509 ;
     RECT  50.652 27.163 50.67 27.595 ;
     RECT  43.164 27.401 43.182 27.635 ;
     RECT  47.016 27.509 47.574 27.715 ;
     RECT  48.456 27.481 48.69 27.715 ;
     RECT  47.016 27.715 48.69 27.743 ;
     RECT  47.16 27.743 48.69 27.751 ;
     RECT  47.16 27.751 49.374 27.869 ;
     RECT  50.652 27.595 50.706 27.869 ;
     RECT  47.16 27.869 47.178 27.905 ;
     RECT  48.276 27.869 49.374 27.905 ;
     RECT  2.268 26.599 8.766 27.977 ;
     RECT  50.688 27.869 50.706 28.139 ;
     RECT  48.276 27.905 49.338 28.175 ;
     RECT  49.32 28.175 49.338 28.211 ;
     RECT  24.015 2.413 24.297 28.921 ;
     RECT  24.015 28.921 24.786 29.021 ;
     RECT  2.304 27.977 8.766 29.131 ;
     RECT  18.216 27.341 18.897 29.227 ;
     RECT  2.232 29.131 8.766 29.255 ;
     RECT  25.884 29.029 25.902 29.309 ;
     RECT  12.348 29.221 12.366 29.371 ;
     RECT  13.215 2.413 13.497 29.371 ;
     RECT  10.836 29.275 10.854 29.405 ;
     RECT  12.348 29.371 13.497 29.405 ;
     RECT  12.636 29.405 13.497 29.645 ;
     RECT  17.676 29.227 18.897 29.645 ;
     RECT  16.452 26.159 16.47 31.483 ;
     RECT  15.912 31.483 16.47 31.495 ;
     RECT  15.912 31.495 16.722 31.531 ;
     RECT  11.196 31.495 11.214 31.649 ;
     RECT  14.832 31.621 14.85 31.721 ;
     RECT  15.912 31.531 17.19 31.721 ;
     RECT  2.304 29.255 8.766 31.919 ;
     RECT  2.304 31.919 6.786 32.495 ;
     RECT  15.912 31.721 16.47 32.575 ;
     RECT  15.912 32.575 16.722 32.603 ;
     RECT  15.984 32.603 16.722 32.611 ;
     RECT  11.772 32.467 11.79 32.729 ;
     RECT  14.796 32.737 14.814 32.837 ;
     RECT  2.376 32.495 6.318 33.269 ;
     RECT  15.984 32.611 17.19 33.349 ;
     RECT  2.376 33.269 6.282 33.385 ;
     RECT  11.376 32.971 11.394 33.421 ;
     RECT  11.268 33.421 11.394 33.575 ;
     RECT  15.948 33.349 17.442 33.583 ;
     RECT  18.216 29.645 18.897 33.583 ;
     RECT  15.948 33.583 18.897 33.655 ;
     RECT  15.804 33.655 18.897 33.725 ;
     RECT  7.632 31.919 8.766 33.809 ;
     RECT  12.42 33.691 12.438 33.809 ;
     RECT  2.304 33.385 6.282 34.079 ;
     RECT  6.264 34.079 6.282 34.087 ;
     RECT  12.276 33.925 12.294 34.115 ;
     RECT  14.832 34.087 14.85 34.187 ;
     RECT  11.304 33.575 11.394 34.231 ;
     RECT  11.304 34.231 11.718 34.385 ;
     RECT  11.304 34.385 11.322 34.529 ;
     RECT  6.264 34.087 6.858 34.889 ;
     RECT  6.84 34.889 6.858 35.069 ;
     RECT  12.168 34.897 12.33 35.159 ;
     RECT  2.304 34.079 5.454 35.179 ;
     RECT  12.168 35.159 12.186 35.195 ;
     RECT  16.056 33.725 18.897 35.429 ;
     RECT  2.196 35.179 5.454 35.465 ;
     RECT  7.668 33.809 8.766 36.509 ;
     RECT  18.216 35.429 18.897 36.509 ;
     RECT  7.668 36.509 8.622 36.517 ;
     RECT  7.488 36.517 8.622 36.523 ;
     RECT  6.84 36.523 8.622 36.557 ;
     RECT  11.304 36.523 11.322 36.619 ;
     RECT  18.396 36.509 18.897 36.625 ;
     RECT  6.84 36.557 6.858 36.653 ;
     RECT  7.668 36.557 8.622 36.689 ;
     RECT  2.304 35.465 5.454 36.751 ;
     RECT  13.215 29.645 13.497 36.751 ;
     RECT  18.396 36.625 18.954 36.779 ;
     RECT  10.8 36.619 11.322 36.797 ;
     RECT  12.744 36.751 13.497 36.797 ;
     RECT  2.304 36.751 5.814 36.895 ;
     RECT  18.54 36.779 18.954 36.895 ;
     RECT  2.268 36.895 5.814 36.931 ;
     RECT  2.268 36.931 6.174 36.941 ;
     RECT  11.304 36.797 11.322 37.049 ;
     RECT  2.304 36.941 6.174 37.157 ;
     RECT  2.304 37.157 5.454 38.705 ;
     RECT  2.34 38.705 5.454 39.479 ;
     RECT  2.34 39.479 3.942 39.883 ;
     RECT  0.108 39.865 0.126 39.965 ;
     RECT  4.68 39.479 5.454 40.019 ;
     RECT  6.84 40.021 6.858 40.171 ;
     RECT  7.704 36.689 8.622 40.171 ;
     RECT  16.056 35.429 17.37 40.289 ;
     RECT  18.54 36.895 19.062 40.405 ;
     RECT  20.196 35.239 20.214 40.531 ;
     RECT  2.304 39.883 3.942 40.595 ;
     RECT  4.752 40.019 5.454 40.651 ;
     RECT  4.752 40.651 5.742 40.675 ;
     RECT  6.84 40.171 8.622 40.675 ;
     RECT  20.196 40.531 20.538 40.675 ;
     RECT  3.636 40.595 3.942 40.711 ;
     RECT  19.944 40.675 20.826 40.711 ;
     RECT  19.944 40.711 21.258 40.733 ;
     RECT  3.636 40.711 4.014 40.801 ;
     RECT  4.752 40.675 8.622 40.801 ;
     RECT  2.304 40.595 2.862 40.829 ;
     RECT  16.344 40.289 17.37 40.829 ;
     RECT  14.436 40.675 14.454 40.901 ;
     RECT  19.98 40.733 21.258 40.901 ;
     RECT  3.636 40.801 8.622 41.135 ;
     RECT  7.632 41.135 8.622 41.207 ;
     RECT  16.38 40.829 17.37 41.369 ;
     RECT  16.776 41.369 17.37 41.485 ;
     RECT  18.504 40.405 19.062 41.485 ;
     RECT  19.98 40.901 20.61 41.485 ;
     RECT  7.632 41.207 8.406 41.675 ;
     RECT  2.304 40.829 2.79 41.707 ;
     RECT  3.636 41.135 6.822 41.707 ;
     RECT  2.304 41.707 6.822 41.945 ;
     RECT  16.776 41.485 17.73 42.173 ;
     RECT  3.42 41.945 6.822 42.449 ;
     RECT  10.512 42.187 10.53 42.449 ;
     RECT  3.456 42.449 6.822 42.521 ;
     RECT  3.456 42.521 3.474 42.593 ;
     RECT  4.248 42.521 6.822 42.601 ;
     RECT  7.704 41.675 8.406 42.601 ;
     RECT  11.376 42.427 11.394 42.601 ;
     RECT  11.376 42.601 12.078 42.653 ;
     RECT  11.376 42.653 11.394 42.719 ;
     RECT  4.248 42.601 8.406 42.8 ;
     RECT  5.256 42.8 8.406 42.863 ;
     RECT  4.248 42.8 4.446 43.025 ;
     RECT  4.428 43.025 4.446 43.061 ;
     RECT  6.804 42.863 8.406 43.259 ;
     RECT  2.304 41.945 2.697 43.295 ;
     RECT  6.804 43.259 8.298 43.331 ;
     RECT  7.776 43.331 8.298 43.367 ;
     RECT  6.804 43.331 6.822 43.529 ;
     RECT  7.815 43.367 8.298 43.529 ;
     RECT  5.256 42.863 5.706 43.565 ;
     RECT  5.256 43.565 5.562 44.069 ;
     RECT  18.504 41.485 20.61 44.419 ;
     RECT  17.712 42.173 17.73 44.443 ;
     RECT  16.776 42.173 16.83 44.959 ;
     RECT  17.676 44.443 17.73 44.959 ;
     RECT  16.776 44.959 17.73 45.005 ;
     RECT  5.544 44.069 5.562 46.031 ;
     RECT  5.688 46.111 5.706 46.499 ;
     RECT  16.776 45.005 16.83 46.507 ;
     RECT  26.784 46.459 26.802 46.589 ;
     RECT  13.215 36.797 13.497 46.615 ;
     RECT  30.528 46.543 30.546 46.651 ;
     RECT  30.528 46.651 30.798 46.741 ;
     RECT  13.215 46.615 13.59 46.781 ;
     RECT  30.528 46.741 30.87 46.781 ;
     RECT  16.668 46.507 16.83 46.813 ;
     RECT  17.712 45.005 17.73 46.813 ;
     RECT  24.015 29.021 24.297 46.921 ;
     RECT  25.992 46.843 26.01 46.921 ;
     RECT  25.992 46.921 26.586 47.011 ;
     RECT  16.668 46.813 17.73 47.035 ;
     RECT  18.504 44.419 20.646 47.035 ;
     RECT  25.74 47.011 26.586 47.155 ;
     RECT  15.804 42.727 15.822 47.281 ;
     RECT  29.415 2.413 29.697 47.281 ;
     RECT  24.015 46.921 24.39 47.317 ;
     RECT  25.56 47.155 26.586 47.317 ;
     RECT  16.668 47.035 20.646 47.323 ;
     RECT  15.804 47.281 15.894 47.353 ;
     RECT  16.668 47.323 20.754 47.353 ;
     RECT  22.968 47.317 23.094 47.353 ;
     RECT  38.376 47.191 38.394 47.353 ;
     RECT  30.528 46.781 30.546 47.357 ;
     RECT  24.015 47.317 26.586 47.371 ;
     RECT  22.716 47.353 23.094 47.389 ;
     RECT  28.476 47.281 29.79 47.389 ;
     RECT  15.804 47.353 20.754 47.419 ;
     RECT  38.196 47.353 38.394 47.425 ;
     RECT  22.716 47.389 23.166 47.461 ;
     RECT  24.015 47.371 26.766 47.461 ;
     RECT  33.876 47.389 33.894 47.461 ;
     RECT  34.815 2.413 35.097 47.461 ;
     RECT  22.572 47.461 23.166 47.551 ;
     RECT  24.015 47.461 26.874 47.551 ;
     RECT  36.54 47.461 36.558 47.587 ;
     RECT  15.804 47.419 20.862 47.623 ;
     RECT  28.476 47.389 30.186 47.623 ;
     RECT  15.804 47.623 21.114 47.659 ;
     RECT  31.716 47.623 31.734 47.659 ;
     RECT  31.716 47.659 31.95 47.695 ;
     RECT  36.36 47.587 36.558 47.695 ;
     RECT  22.248 47.551 26.874 47.731 ;
     RECT  31.716 47.695 32.382 47.731 ;
     RECT  33.876 47.461 35.097 47.731 ;
     RECT  38.196 47.425 38.43 47.731 ;
     RECT  31.716 47.731 32.886 47.803 ;
     RECT  33.804 47.731 35.478 47.803 ;
     RECT  15.408 47.659 21.114 47.821 ;
     RECT  28.26 47.623 30.186 47.821 ;
     RECT  36.36 47.695 36.702 47.821 ;
     RECT  37.476 47.731 38.43 47.821 ;
     RECT  30.996 47.803 35.478 47.849 ;
     RECT  36.36 47.821 38.43 47.849 ;
     RECT  21.888 47.731 26.874 47.851 ;
     RECT  27.828 47.821 30.186 47.851 ;
     RECT  32.868 47.849 35.478 47.965 ;
     RECT  36.36 47.849 38.214 47.965 ;
     RECT  21.888 47.851 30.186 48.029 ;
     RECT  30.996 47.849 31.95 48.119 ;
     RECT  32.868 47.965 38.214 48.119 ;
     RECT  13.215 46.781 13.497 48.139 ;
     RECT  13.215 48.139 13.914 48.199 ;
     RECT  14.832 47.821 21.114 48.199 ;
     RECT  27 48.029 30.186 48.227 ;
     RECT  27 48.227 29.79 48.263 ;
     RECT  30.996 48.119 31.734 48.271 ;
     RECT  13.215 48.199 21.114 48.361 ;
     RECT  21.888 48.029 26.226 48.361 ;
     RECT  27 48.263 29.697 48.389 ;
     RECT  30.564 48.271 31.734 48.389 ;
     RECT  34.815 48.119 38.178 48.389 ;
     RECT  32.868 48.119 34.002 48.659 ;
     RECT  32.868 48.659 33.75 49.199 ;
     RECT  34.815 48.389 36.126 49.199 ;
     RECT  37.188 48.389 38.178 49.199 ;
     RECT  13.215 48.361 26.226 49.315 ;
     RECT  27.288 48.389 29.697 49.315 ;
     RECT  13.215 49.315 29.697 49.351 ;
     RECT  30.708 48.389 31.59 49.351 ;
     RECT  32.868 49.199 33.714 49.351 ;
     RECT  37.188 49.199 38.034 49.351 ;
     RECT  2.415 43.295 2.697 49.427 ;
     RECT  7.815 43.529 8.097 49.427 ;
     RECT  40.215 2.413 40.497 49.427 ;
     RECT  45.615 27.509 45.897 49.427 ;
     RECT  13.032 49.351 31.59 49.435 ;
     RECT  12.888 49.435 31.59 49.469 ;
     RECT  32.544 49.351 33.714 49.469 ;
     RECT  34.815 49.199 35.874 49.469 ;
     RECT  36.864 49.351 38.034 49.469 ;
     RECT  12.888 49.469 31.158 49.505 ;
     RECT  13.215 49.505 31.158 49.517 ;
     RECT  32.544 49.469 33.534 49.517 ;
     RECT  34.815 49.469 35.694 49.517 ;
     RECT  36.864 49.469 37.854 49.517 ;
     RECT  13.215 49.517 17.874 49.541 ;
     RECT  34.815 49.517 34.905 49.549 ;
     RECT  14.436 49.541 17.874 49.565 ;
     RECT  20.376 49.517 28.134 49.565 ;
     RECT  29.415 49.517 31.158 49.565 ;
     RECT  14.436 49.565 17.478 49.577 ;
     RECT  18.615 49.517 19.422 49.577 ;
     RECT  20.376 49.565 25.902 49.577 ;
     RECT  26.856 49.565 27.738 49.577 ;
     RECT  29.415 49.565 30.222 49.577 ;
     RECT  36.684 49.531 36.702 49.577 ;
     RECT  2.415 49.427 2.505 49.697 ;
     RECT  7.815 49.427 7.905 49.697 ;
     RECT  13.215 49.541 13.305 49.697 ;
     RECT  18.615 49.577 18.705 49.697 ;
     RECT  23.832 49.577 24.105 49.697 ;
     RECT  29.415 49.577 29.505 49.697 ;
     RECT  34.74 49.549 34.905 49.697 ;
     RECT  40.215 49.427 40.305 49.697 ;
     RECT  45.615 49.427 45.705 49.697 ;
     RECT  34.74 49.697 34.758 49.853 ;
     RECT  27.288 49.577 27.306 50.189 ;
     RECT  14.76 49.577 14.778 50.765 ;
     RECT  16.488 49.577 16.506 50.765 ;
     RECT  22.104 49.577 22.122 50.765 ;
     RECT  23.832 49.697 23.85 50.765 ;
     RECT  25.02 49.577 25.326 50.765 ;
     RECT  32.364 49.549 32.382 50.765 ;
     RECT  25.308 50.765 25.326 50.813 ;
    LAYER M4 ;
     RECT  0.06 8.832 0.133 42.984 ;
     RECT  0.133 8.496 0.227 42.984 ;
     RECT  0.227 8.496 2.408 38.664 ;
     RECT  0.227 39.888 2.408 42.984 ;
     RECT  2.408 2.148 2.512 49.692 ;
     RECT  2.512 2.418 2.704 49.422 ;
     RECT  2.704 8.352 2.867 13.128 ;
     RECT  2.704 14.208 2.963 41.736 ;
     RECT  2.867 9.072 3.107 13.128 ;
     RECT  3.107 9.072 3.161 10.392 ;
     RECT  2.963 14.208 3.203 34.776 ;
     RECT  3.161 9.072 3.305 9.096 ;
     RECT  3.107 11.52 3.347 13.128 ;
     RECT  2.963 35.904 3.347 41.736 ;
     RECT  3.203 14.208 3.413 14.952 ;
     RECT  3.347 11.856 3.587 13.128 ;
     RECT  3.161 10.224 3.593 10.392 ;
     RECT  3.347 35.904 3.683 39.576 ;
     RECT  3.683 38.208 3.701 39.576 ;
     RECT  3.593 10.224 3.731 10.248 ;
     RECT  3.701 38.208 3.731 38.808 ;
     RECT  3.203 15.984 3.845 34.776 ;
     RECT  3.683 35.904 3.997 37.08 ;
     RECT  3.845 15.984 4.061 34.152 ;
     RECT  4.061 15.984 4.115 32.568 ;
     RECT  3.413 14.256 4.165 14.952 ;
     RECT  4.115 15.984 4.165 17.112 ;
     RECT  4.115 18.24 4.169 32.568 ;
     RECT  4.169 25.68 4.241 32.568 ;
     RECT  4.061 33.648 4.241 34.152 ;
     RECT  4.165 14.256 4.307 17.112 ;
     RECT  4.307 14.256 4.355 14.952 ;
     RECT  4.169 18.24 4.421 24.648 ;
     RECT  4.307 16.368 4.601 17.112 ;
     RECT  4.241 25.68 4.601 32.472 ;
     RECT  4.421 20.208 4.637 24.648 ;
     RECT  3.587 12.48 4.643 13.128 ;
     RECT  4.637 20.208 4.673 23.592 ;
     RECT  4.601 26.736 4.739 32.472 ;
     RECT  4.643 13.104 4.781 13.128 ;
     RECT  4.739 31.92 4.817 32.472 ;
     RECT  4.421 18.24 4.853 18.936 ;
     RECT  4.739 26.736 4.853 30.84 ;
     RECT  4.673 20.352 4.883 23.592 ;
     RECT  4.853 26.736 4.961 30.264 ;
     RECT  4.817 31.92 4.979 32.28 ;
     RECT  3.731 38.208 4.979 38.232 ;
     RECT  4.883 21.12 5.033 23.592 ;
     RECT  4.601 25.68 5.033 25.704 ;
     RECT  4.961 26.736 5.033 29.304 ;
     RECT  4.637 24.624 5.068 24.648 ;
     RECT  4.849 42.336 5.093 42.36 ;
     RECT  5.093 42.336 5.101 42.792 ;
     RECT  4.853 18.816 5.105 18.936 ;
     RECT  5.033 26.736 5.105 27.192 ;
     RECT  5.101 41.76 5.171 42.792 ;
     RECT  5.033 21.648 5.177 23.592 ;
     RECT  5.171 42.768 5.177 42.792 ;
     RECT  5.177 21.648 5.213 21.768 ;
     RECT  4.241 33.648 5.213 33.672 ;
     RECT  4.601 17.088 5.353 17.112 ;
     RECT  5.105 26.832 5.357 27.192 ;
     RECT  3.347 40.752 5.389 40.776 ;
     RECT  5.105 18.912 5.429 18.936 ;
     RECT  5.357 26.928 5.537 27.192 ;
     RECT  5.033 28.272 5.609 29.304 ;
     RECT  4.355 14.928 5.699 14.952 ;
     RECT  5.353 17.088 5.699 17.688 ;
     RECT  4.979 31.92 5.725 31.944 ;
     RECT  5.389 40.656 5.753 40.776 ;
     RECT  5.699 17.088 5.825 17.112 ;
     RECT  3.997 36.624 6.185 37.08 ;
     RECT  5.753 40.752 6.473 40.776 ;
     RECT  5.171 41.76 6.716 41.784 ;
     RECT  6.716 41.472 6.757 41.784 ;
     RECT  5.537 27.168 6.793 27.192 ;
     RECT  6.757 41.472 6.803 42.456 ;
     RECT  6.185 36.624 6.829 36.792 ;
     RECT  6.793 27.12 6.901 27.192 ;
     RECT  5.213 21.648 7.045 21.672 ;
     RECT  6.901 27.072 7.297 27.192 ;
     RECT  6.803 42.192 7.405 42.456 ;
     RECT  5.609 28.512 7.669 29.304 ;
     RECT  7.045 21.072 7.808 21.672 ;
     RECT  5.177 22.992 7.808 23.592 ;
     RECT  7.297 27.072 7.808 27.384 ;
     RECT  7.669 28.512 7.808 29.64 ;
     RECT  6.829 36.528 7.808 36.792 ;
     RECT  6.829 40.032 7.808 40.056 ;
     RECT  7.405 42.192 7.808 42.792 ;
     RECT  7.808 2.148 7.912 49.692 ;
     RECT  7.912 2.418 8.104 49.422 ;
     RECT  8.104 42.192 8.201 42.552 ;
     RECT  8.201 42.192 10.541 42.456 ;
     RECT  8.104 36.528 10.789 36.648 ;
     RECT  8.104 29.28 10.865 29.64 ;
     RECT  10.789 36.528 11.333 36.792 ;
     RECT  10.541 42.432 11.365 42.456 ;
     RECT  11.365 42.432 11.405 42.648 ;
     RECT  10.865 29.376 12.337 29.64 ;
     RECT  8.104 22.992 13.208 23.592 ;
     RECT  8.104 27.168 13.208 27.192 ;
     RECT  12.337 29.232 13.208 29.64 ;
     RECT  11.333 36.768 13.208 36.792 ;
     RECT  11.405 42.624 13.208 42.648 ;
     RECT  12.757 48.144 13.208 48.168 ;
     RECT  12.757 49.44 13.208 49.464 ;
     RECT  13.208 2.148 13.312 49.692 ;
     RECT  13.312 2.418 13.504 49.422 ;
     RECT  13.504 48.144 13.925 48.504 ;
     RECT  14.749 50.736 14.915 50.76 ;
     RECT  13.925 48.48 15.005 48.504 ;
     RECT  13.504 46.752 15.397 46.776 ;
     RECT  15.793 33.696 16.076 33.72 ;
     RECT  16.076 33.696 16.213 34.344 ;
     RECT  16.213 33.696 16.259 35.304 ;
     RECT  13.504 36.768 16.259 36.792 ;
     RECT  16.477 50.736 16.643 50.76 ;
     RECT  15.397 46.752 16.657 47.688 ;
     RECT  13.504 22.992 16.801 23.592 ;
     RECT  16.259 35.28 16.913 35.304 ;
     RECT  16.259 33.696 17.129 33.72 ;
     RECT  17.305 42.144 17.389 42.168 ;
     RECT  17.317 44.448 17.449 44.472 ;
     RECT  17.449 44.448 17.555 45 ;
     RECT  15.973 25.728 17.605 25.752 ;
     RECT  13.504 28.992 17.653 29.256 ;
     RECT  13.504 27.168 17.701 27.192 ;
     RECT  16.657 46.512 18.181 47.688 ;
     RECT  14.396 49.536 18.325 49.56 ;
     RECT  16.801 22.992 18.608 23.688 ;
     RECT  17.605 25.488 18.608 25.752 ;
     RECT  17.701 27.12 18.608 27.192 ;
     RECT  17.653 28.992 18.608 29.64 ;
     RECT  15.901 31.488 18.608 31.512 ;
     RECT  17.555 44.448 18.608 44.472 ;
     RECT  18.181 46.512 18.608 48.504 ;
     RECT  18.325 49.488 18.608 49.56 ;
     RECT  18.608 2.148 18.712 49.692 ;
     RECT  18.712 2.418 18.904 49.56 ;
     RECT  18.904 25.488 19.001 25.608 ;
     RECT  18.904 27.12 19.001 27.336 ;
     RECT  18.904 46.176 19.045 47.448 ;
     RECT  18.904 40.704 19.973 40.728 ;
     RECT  18.904 49.536 20.053 49.56 ;
     RECT  20.053 49.488 20.153 49.56 ;
     RECT  19.045 46.512 20.297 47.448 ;
     RECT  20.297 46.752 20.873 47.448 ;
     RECT  22.093 50.736 22.259 50.76 ;
     RECT  20.873 46.752 22.777 47.4 ;
     RECT  23.821 50.736 23.987 50.76 ;
     RECT  18.904 22.992 24.008 23.016 ;
     RECT  19.001 25.584 24.008 25.608 ;
     RECT  19.001 27.168 24.008 27.336 ;
     RECT  18.904 28.992 24.008 29.304 ;
     RECT  22.777 46.752 24.008 47.88 ;
     RECT  20.153 49.536 24.008 49.56 ;
     RECT  24.008 2.148 24.112 49.692 ;
     RECT  24.112 2.418 24.304 49.56 ;
     RECT  24.304 28.992 24.797 29.304 ;
     RECT  24.304 49.536 24.851 49.56 ;
     RECT  25.009 50.736 25.282 50.76 ;
     RECT  25.282 50.736 25.283 50.808 ;
     RECT  25.283 50.784 25.715 50.808 ;
     RECT  24.797 29.28 25.813 29.304 ;
     RECT  24.304 46.848 25.909 48.12 ;
     RECT  25.813 29.28 25.913 29.64 ;
     RECT  25.913 29.616 25.955 29.64 ;
     RECT  25.909 46.464 26.777 48.12 ;
     RECT  26.777 46.464 26.813 46.584 ;
     RECT  25.873 49.536 27.277 49.56 ;
     RECT  26.777 47.856 27.353 48.12 ;
     RECT  27.277 49.536 27.443 50.184 ;
     RECT  27.443 49.536 28.307 49.56 ;
     RECT  26.813 46.56 29.257 46.584 ;
     RECT  27.353 47.856 29.257 47.88 ;
     RECT  24.304 22.992 29.408 23.016 ;
     RECT  24.304 25.584 29.408 25.608 ;
     RECT  24.304 27.168 29.408 27.336 ;
     RECT  29.257 46.56 29.408 47.88 ;
     RECT  28.693 49.488 29.408 49.512 ;
     RECT  29.408 2.148 29.512 49.692 ;
     RECT  29.512 2.418 29.704 49.56 ;
     RECT  29.704 46.56 30.557 47.352 ;
     RECT  30.557 46.752 30.805 47.352 ;
     RECT  30.805 46.752 30.851 47.832 ;
     RECT  30.851 46.752 30.881 46.776 ;
     RECT  29.704 49.536 31.331 49.56 ;
     RECT  32.353 50.736 32.627 50.76 ;
     RECT  33.013 49.488 33.545 49.512 ;
     RECT  30.851 47.808 33.577 47.832 ;
     RECT  33.577 47.808 33.617 47.928 ;
     RECT  34.7 49.824 34.787 49.848 ;
     RECT  29.704 22.992 34.808 23.016 ;
     RECT  29.704 25.584 34.808 25.608 ;
     RECT  29.704 27.168 34.808 27.336 ;
     RECT  33.617 47.904 34.808 47.928 ;
     RECT  34.808 2.148 34.912 49.692 ;
     RECT  34.912 2.418 35.104 49.512 ;
     RECT  35.104 47.904 35.345 48.36 ;
     RECT  35.104 49.488 35.705 49.512 ;
     RECT  36.673 49.536 36.947 49.56 ;
     RECT  35.345 48.336 37.073 48.36 ;
     RECT  37.333 49.488 37.865 49.512 ;
     RECT  35.104 22.992 40.208 23.016 ;
     RECT  35.104 25.584 40.208 25.608 ;
     RECT  35.104 27.168 40.208 27.336 ;
     RECT  40.208 2.148 40.312 49.692 ;
     RECT  40.312 2.418 40.504 49.422 ;
     RECT  40.504 27.168 42.361 27.336 ;
     RECT  42.361 26.736 42.401 27.336 ;
     RECT  42.401 26.736 42.545 27.192 ;
     RECT  40.504 25.584 43.909 25.608 ;
     RECT  43.909 25.104 43.949 25.608 ;
     RECT  43.949 25.104 45.529 25.128 ;
     RECT  42.545 26.736 45.529 26.76 ;
     RECT  40.504 22.992 45.601 23.016 ;
     RECT  45.601 22.992 45.608 23.112 ;
     RECT  45.529 24.48 45.608 25.128 ;
     RECT  45.529 26.256 45.608 26.76 ;
     RECT  45.608 2.148 45.712 49.692 ;
     RECT  45.712 2.418 45.904 49.422 ;
     RECT  47.005 27.36 47.171 27.384 ;
     RECT  45.904 24.48 47.189 24.504 ;
     RECT  45.904 26.256 47.189 26.28 ;
     RECT  50.137 26.304 50.641 26.328 ;
     RECT  50.173 24.576 50.677 24.6 ;
     RECT  50.641 26.304 50.677 27.192 ;
     RECT  50.677 24.144 51.804 27.624 ;
    LAYER M5 ;
     RECT  2.4 2.137 2.52 2.151 ;
     RECT  7.8 2.137 7.92 2.151 ;
     RECT  13.2 2.137 13.32 2.151 ;
     RECT  18.6 2.137 18.72 2.151 ;
     RECT  24 2.137 24.12 2.151 ;
     RECT  29.4 2.137 29.52 2.151 ;
     RECT  34.8 2.137 34.92 2.151 ;
     RECT  40.2 2.137 40.32 2.151 ;
     RECT  45.6 2.137 45.72 2.151 ;
     RECT  2.4 2.151 2.712 8.341 ;
     RECT  2.4 8.341 2.856 9.061 ;
     RECT  0.144 8.485 0.168 9.637 ;
     RECT  2.4 9.061 2.904 9.925 ;
     RECT  2.4 9.925 3.048 10.069 ;
     RECT  0.144 9.637 0.264 10.163 ;
     RECT  2.304 10.069 3.048 10.213 ;
     RECT  0.144 10.163 0.168 10.307 ;
     RECT  0.144 11.413 0.168 12.035 ;
     RECT  2.304 10.213 3.72 12.469 ;
     RECT  0.144 13.573 0.168 13.715 ;
     RECT  0.144 15.301 0.168 16.019 ;
     RECT  2.304 12.469 4.632 17.077 ;
     RECT  5.664 14.917 5.688 17.077 ;
     RECT  2.304 17.077 5.688 17.699 ;
     RECT  2.304 17.699 4.92 18.851 ;
     RECT  0.144 17.029 0.168 19.427 ;
     RECT  7.8 2.151 8.112 21.061 ;
     RECT  2.4 18.851 4.92 21.637 ;
     RECT  0.144 20.917 0.168 21.683 ;
     RECT  7.056 21.061 8.112 21.683 ;
     RECT  0.528 22.117 0.552 22.259 ;
     RECT  2.4 21.637 5.112 22.499 ;
     RECT  2.4 22.499 4.92 22.741 ;
     RECT  0.144 22.645 0.168 22.835 ;
     RECT  7.2 21.683 8.112 23.075 ;
     RECT  18.6 2.151 18.912 23.269 ;
     RECT  2.304 22.741 4.92 23.557 ;
     RECT  2.304 23.557 5.016 24.659 ;
     RECT  17.616 23.269 18.912 25.523 ;
     RECT  0.144 26.101 0.168 26.243 ;
     RECT  7.8 23.075 8.112 27.349 ;
     RECT  47.136 26.245 47.16 27.395 ;
     RECT  0.144 27.829 0.168 27.971 ;
     RECT  2.304 24.659 4.92 28.501 ;
     RECT  2.304 28.501 5.688 28.547 ;
     RECT  13.2 2.151 13.512 28.981 ;
     RECT  15.072 23.317 15.096 29.267 ;
     RECT  7.68 27.349 8.112 29.269 ;
     RECT  17.712 25.523 18.912 29.605 ;
     RECT  25.824 29.269 25.848 29.605 ;
     RECT  25.824 29.605 25.944 29.651 ;
     RECT  2.4 28.547 5.688 30.325 ;
     RECT  17.664 29.605 18.912 31.523 ;
     RECT  2.304 30.325 5.688 31.955 ;
     RECT  0.144 29.557 0.168 32.437 ;
     RECT  0.144 32.437 0.264 33.059 ;
     RECT  0.144 33.059 0.168 33.107 ;
     RECT  16.128 33.685 16.152 34.309 ;
     RECT  16.128 34.309 16.248 34.355 ;
     RECT  0.144 34.741 0.168 34.883 ;
     RECT  2.304 31.955 4.968 35.219 ;
     RECT  7.104 29.269 8.112 36.757 ;
     RECT  16.224 34.355 16.248 36.803 ;
     RECT  2.4 35.219 4.968 38.243 ;
     RECT  2.4 38.243 3.72 38.819 ;
     RECT  0.144 39.061 0.168 39.493 ;
     RECT  18.6 31.523 18.912 40.693 ;
     RECT  0.144 39.493 0.216 41.075 ;
     RECT  0.144 41.075 0.168 41.171 ;
     RECT  6.864 36.757 8.112 41.461 ;
     RECT  2.4 38.819 3.336 41.747 ;
     RECT  6.768 41.461 8.112 42.467 ;
     RECT  13.2 28.981 14.04 42.613 ;
     RECT  5.136 40.741 5.16 42.803 ;
     RECT  7.44 42.467 8.112 42.803 ;
     RECT  17.328 42.133 17.352 44.483 ;
     RECT  18.6 40.693 19.032 46.211 ;
     RECT  25.92 29.651 25.944 46.883 ;
     RECT  17.52 44.965 17.544 47.221 ;
     RECT  18.6 46.211 18.912 47.221 ;
     RECT  17.52 47.221 18.912 47.363 ;
     RECT  30.816 47.317 30.84 47.843 ;
     RECT  18.192 47.363 18.912 48.515 ;
     RECT  12.768 42.613 14.04 49.475 ;
     RECT  18.6 48.515 18.912 49.477 ;
     RECT  29.4 2.151 29.712 49.477 ;
     RECT  34.8 2.151 35.112 49.477 ;
     RECT  13.2 49.475 14.04 49.525 ;
     RECT  18.336 49.477 18.912 49.525 ;
     RECT  20.064 49.477 20.088 49.525 ;
     RECT  24 2.151 24.312 49.525 ;
     RECT  28.704 49.477 29.712 49.525 ;
     RECT  37.344 49.477 37.8 49.525 ;
     RECT  2.4 41.747 2.712 49.689 ;
     RECT  7.8 42.803 8.112 49.689 ;
     RECT  40.2 2.151 40.512 49.689 ;
     RECT  45.6 2.151 45.912 49.689 ;
     RECT  2.4 49.689 2.52 49.703 ;
     RECT  7.8 49.689 7.92 49.703 ;
     RECT  13.2 49.525 24.84 49.703 ;
     RECT  26.112 49.525 31.32 49.703 ;
     RECT  40.2 49.689 40.32 49.703 ;
     RECT  45.6 49.689 45.72 49.703 ;
     RECT  34.8 49.477 35.64 49.813 ;
     RECT  19.632 49.703 24.84 50.725 ;
     RECT  26.112 49.703 29.16 50.725 ;
     RECT  33.024 49.477 33.48 50.725 ;
     RECT  14.016 49.703 18.36 51.792 ;
     RECT  19.632 50.725 29.16 51.792 ;
     RECT  30.432 49.703 31.32 51.792 ;
     RECT  32.592 50.725 33.48 51.792 ;
     RECT  34.752 49.813 35.64 51.792 ;
     RECT  36.912 49.525 37.8 51.792 ;
     RECT  0.144 10.307 0.168 11.413 ;
     RECT  4.632 14.917 5.664 17.077 ;
     RECT  0.144 16.019 0.168 17.029 ;
     RECT  0.144 19.427 0.168 20.917 ;
     RECT  0.144 21.683 0.168 22.117 ;
     RECT  0.144 22.117 0.528 22.259 ;
     RECT  0.144 22.259 0.168 22.645 ;
     RECT  4.92 22.499 5.016 23.557 ;
     RECT  45.912 26.245 47.136 27.395 ;
     RECT  14.04 28.981 15.072 29.267 ;
     RECT  5.688 29.269 7.104 31.955 ;
     RECT  24.312 29.269 25.824 29.651 ;
     RECT  17.352 42.133 18.6 44.483 ;
     RECT  17.52 44.483 18.6 44.965 ;
     RECT  17.544 44.965 18.6 47.221 ;
     RECT  29.712 47.317 30.816 47.843 ;
     RECT  18.192 48.515 18.6 49.477 ;
     RECT  18.192 49.477 18.336 49.525 ;
     RECT  18.912 49.477 20.064 49.525 ;
     RECT  33.48 49.477 34.8 49.813 ;
     RECT  24.84 49.525 26.112 50.725 ;
     RECT  35.64 49.525 36.912 51.708 ;
     RECT  18.36 49.703 19.632 51.708 ;
     RECT  29.16 49.703 30.432 51.708 ;
     RECT  33.48 49.813 34.752 51.708 ;
     RECT  31.32 50.725 32.592 51.708 ;
     RECT  18.408 51.708 18.72 51.792 ;
     RECT  18.84 51.708 19.152 51.792 ;
     RECT  19.272 51.708 19.584 51.792 ;
     RECT  29.208 51.708 29.52 51.792 ;
     RECT  29.64 51.708 29.952 51.792 ;
     RECT  30.072 51.708 30.384 51.792 ;
     RECT  31.368 51.708 31.68 51.792 ;
     RECT  31.8 51.708 32.112 51.792 ;
     RECT  32.232 51.708 32.544 51.792 ;
     RECT  33.528 51.708 33.84 51.792 ;
     RECT  33.96 51.708 34.272 51.792 ;
     RECT  34.392 51.708 34.704 51.792 ;
     RECT  35.688 51.708 36 51.792 ;
     RECT  36.12 51.708 36.432 51.792 ;
     RECT  36.552 51.708 36.864 51.792 ;
  END
END dsfd_vm_static_read_v1_p
END LIBRARY
